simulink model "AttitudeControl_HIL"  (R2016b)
settings: Solver=FixedStepDiscrete  StartTime=0.0  StopTime=10.0  RelTol=1e-3
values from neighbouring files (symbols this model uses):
  DEG2RAD = 0.0174533    [Init_control.m]
  Kd_PITCH_AgngleRate = 0.001    [Init_control.m]
  Kd_ROLL_AgngleRate = 0.001    [Init_control.m]
  Kd_YAW_AngleRate = 0.00    (= 0)    [Init_control.m]
  Ki_PITCH_AgngleRate = 0.02    [Init_control.m]
  Ki_ROLL_AgngleRate = 0.02    [Init_control.m]
  Ki_YAW_AngleRate = 0.01    [Init_control.m]
  Kp_PITCH_AgngleRate = 0.1    [Init_control.m]
  Kp_PITCH_ANGLE = 6.5    [Init_control.m]
  Kp_ROLL_AgngleRate = 0.1    [Init_control.m]
  Kp_ROLL_ANGLE = 6.5    [Init_control.m]
  Kp_YAW_AngleRate = 0.3    [Init_control.m]
  MAX_CONTROL_ANGLE_PITCH = 35    [Init_control.m]
  MAX_CONTROL_ANGLE_RATE_PITCH = 220    [Init_control.m]
  MAX_CONTROL_ANGLE_RATE_ROLL = 220    [Init_control.m]
  MAX_CONTROL_ANGLE_RATE_Y = 200    [Init_control.m]
  MAX_CONTROL_ANGLE_ROLL = 35    [Init_control.m]
  Saturation_I_RP_Max = 0.3    [Init_control.m]
  Saturation_I_RP_Min = -0.3    [Init_control.m]
  Saturation_I_Y_Max = 0.2    [Init_control.m]
  Saturation_I_Y_Min = -0.2    [Init_control.m]
  THR_HOVER = 0.6085    [Init_control.m]
undefined symbols (not defined in the file or in its folder): DiscIntNeverNeededParam, RGBLED_COLOR_ENUM, RGBLED_MODE_ENUM
libraries: simulink x5, pixhawk_slib_sensors_actuators x4, pixhawk_slib_uORB_RW x1

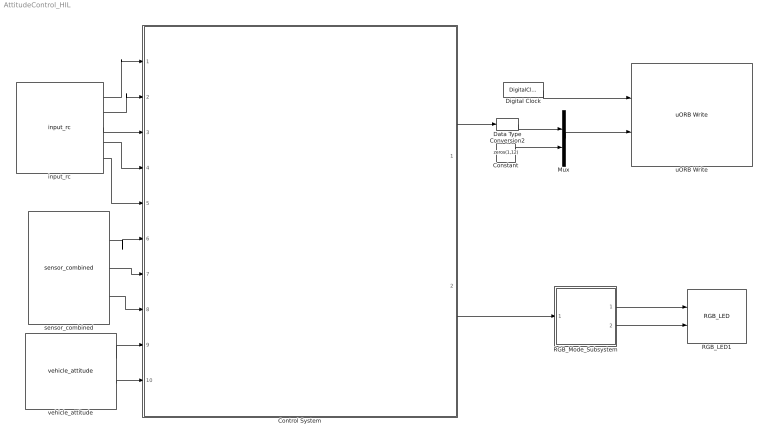
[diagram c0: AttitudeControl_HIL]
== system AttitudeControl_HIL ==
  Constant : Constant  Value=zeros(1,12)
  Control System : Subsystem
  Data Type Conversion2 : DataTypeConversion  OutDataTypeStr=double
  Digital Clock : DigitalClock  SampleTime=-1
  Mux : Mux  Inputs=2
  RGB_LED1 : pixhawk_slib_sensors_actuators/RGB_LED
  RGB_Mode_Subsystem : Subsystem
  input_rc : pixhawk_slib_sensors_actuators/input_rc  sampletime=0.004  channel1=on  channel2=on  channel3=on  channel4=on  channel5=on  channel6=off  channel7=off  channel8=off  ch_count=off  rssi=off  rc_failsafe=off  rc_lost=off  rc_inputsource=off
  sensor_combined : pixhawk_slib_sensors_actuators/sensor_combined  sampletime=0.004  show_mag=off  show_acc=off  show_gyro=on  show_baro=off  show_ts=off
  uORB Write : pixhawk_slib_uORB_RW/uORB Write  uORB_Topic_str='actuator_outputs'  BlockOutputCount=2  OutputBoolean_1=on  uORB_Param_Name1='timestamp'  uORB_Param_Name_DT1=double  VectorScalar_1=1  OutputBoolean_2=on  uORB_Param_Name2='output'  uORB_Param_Name_DT2=double  VectorScalar_2=16  OutputBoolean_3=off  uORB_Param_Name3='timestamp_time'  uORB_Param_Name_DT3=double  VectorScalar_3=1  OutputBoolean_4=off  uORB_Param_Name4='gyro_temp'  uORB_Param_Name_DT4=single  VectorScalar_4=3  OutputBoolean_5=off  uORB_Param_Name5='vel_ned_valid'  uORB_Param_Name_DT5=boolean  VectorScalar_5=1  Ts=-1
  vehicle_attitude : pixhawk_slib_sensors_actuators/vehicle_attitude  sampletime=0.004  show_r=on  show_p=on  show_y=off  show_q=off
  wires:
  sensor_combined/1 -> Control System/6(p)
  sensor_combined/3 -> Control System/8(r)
  vehicle_attitude/1 -> Control System/9(roll)
  vehicle_attitude/2 -> Control System/10(pitch)
  sensor_combined/2 -> Control System/7(q)
  RGB_Mode_Subsystem/1(RGB_MODE) -> RGB_LED1/1
  RGB_Mode_Subsystem/2(RGB_COLOR) -> RGB_LED1/2
  Control System/2(RC_Armed/LED) -> RGB_Mode_Subsystem/1(LED)
  input_rc/1 -> Control System/1(ch1)
  input_rc/2 -> Control System/2(ch2)
  input_rc/3 -> Control System/3(ch3)
  input_rc/4 -> Control System/4(ch4)
  input_rc/5 -> Control System/5(ch5)
  Digital Clock/1 -> uORB Write/1
  Mux/1 -> uORB Write/2
  Control System/1(PWM) -> Data Type Conversion2/1
  Constant/1 -> Mux/2
  Data Type Conversion2/1 -> Mux/1

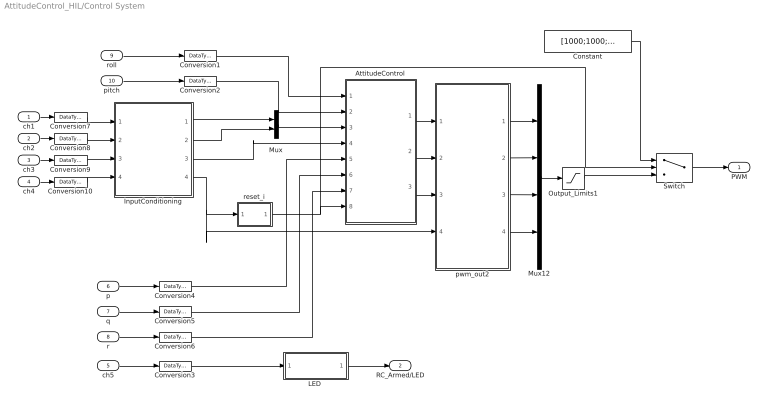
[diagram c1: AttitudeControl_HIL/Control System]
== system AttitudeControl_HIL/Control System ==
  ch1 : Inport  OutDataTypeStr=uint16  PortDimensions=1
  ch2 : Inport  Port=2  OutDataTypeStr=uint16  PortDimensions=1
  ch3 : Inport  Port=3  OutDataTypeStr=uint16  PortDimensions=1
  ch4 : Inport  Port=4  OutDataTypeStr=uint16  PortDimensions=1
  ch5 : Inport  Port=5  OutDataTypeStr=uint16  PortDimensions=1  Interpolate=off
  p : Inport  Port=6  PortDimensions=1
  q : Inport  Port=7  PortDimensions=1
  r : Inport  Port=8  PortDimensions=1
  roll : Inport  Port=9  PortDimensions=1
  pitch : Inport  Port=10  PortDimensions=1
  AttitudeControl : Subsystem
  Constant : Constant  Value=[1000;1000;1000;1000]
  Conversion{1..10} (10 alike) : DataTypeConversion  OutDataTypeStr=double
  InputConditioning : Subsystem
  "LED " : Subsystem
  Mux : Mux  Inputs=2
  Mux12 : Mux
  Output_Limits1 : Saturate  UpperLimit=single(2000)  LowerLimit=single(1000)
  Switch : Switch  Criteria=u2 ~= 0
  pwm_out2 : MATLAB Function  SystemSampleTime=0.004
  reset_i : Subsystem
  PWM : Outport
  RC_Armed/LED : Outport  Port=2  PortDimensions=1
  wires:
  Mux12/1 -> Output_Limits1/1
  AttitudeControl/2(torque_pitch) -> pwm_out2/2(Pitch)
  AttitudeControl/1(torque_roll) -> pwm_out2/1(Roll)
  pwm_out2/1(M1) -> Mux12/1
  pwm_out2/3(M3) -> Mux12/3
  pwm_out2/2(M2) -> Mux12/2
  AttitudeControl/3(torque_yaw) -> pwm_out2/3(Yaw)
  pwm_out2/4(M4) -> Mux12/4
  reset_i/1(Out1) -> AttitudeControl/8(reset_i), Switch/2
  p/1 -> Conversion4/1
  q/1 -> Conversion5/1
  r/1 -> Conversion6/1
  pitch/1 -> Conversion2/1
  roll/1 -> Conversion1/1
  Mux/1 -> AttitudeControl/3(roll_pitch_d)
  "LED "/1(Out1) -> RC_Armed/LED/1
  ch5/1 -> Conversion3/1
  Conversion1/1 -> AttitudeControl/1(phi)
  Conversion2/1 -> AttitudeControl/2(theta)
  Conversion3/1 -> "LED "/1(In1)
  Conversion4/1 -> AttitudeControl/5(p)
  Conversion5/1 -> AttitudeControl/6(q)
  Conversion6/1 -> AttitudeControl/7(r)
  ch3/1 -> Conversion9/1
  ch4/1 -> Conversion10/1
  Conversion10/1 -> InputConditioning/4(r)
  Conversion9/1 -> InputConditioning/3(thrust)
  ch1/1 -> Conversion7/1
  ch2/1 -> Conversion8/1
  InputConditioning/1(Roll) -> Mux/1
  InputConditioning/2(Pitch) -> Mux/2
  InputConditioning/3(Yaw) -> AttitudeControl/4(yawRate_d)
  InputConditioning/4(Thrust) -> pwm_out2/4(Thrust), reset_i/1(In1)
  Conversion7/1 -> InputConditioning/1(roll)
  Conversion8/1 -> InputConditioning/2(pitch)
  Constant/1 -> Switch/1
  Switch/1 -> PWM/1
  Output_Limits1/1 -> Switch/3

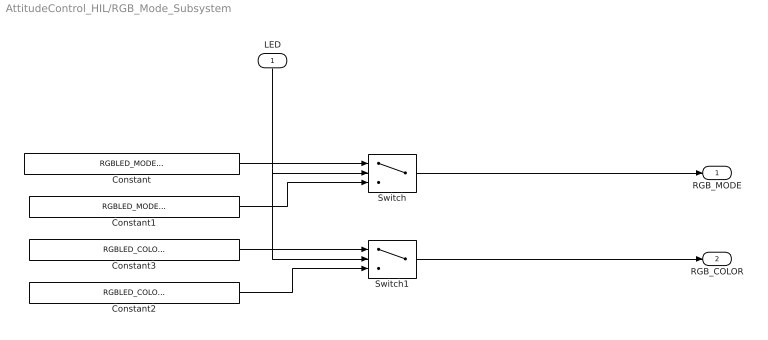
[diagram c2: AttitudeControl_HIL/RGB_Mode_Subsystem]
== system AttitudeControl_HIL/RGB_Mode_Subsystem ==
  LED : Inport
  Constant : Constant  Value=RGBLED_MODE_ENUM.MODE_BLINK_FAST  OutDataTypeStr=Enum: RGBLED_MODE_ENUM
  Constant1 : Constant  Value=RGBLED_MODE_ENUM.MODE_BREATHE  OutDataTypeStr=Enum: RGBLED_MODE_ENUM
  Constant2 : Constant  Value=RGBLED_COLOR_ENUM.COLOR_GREEN  OutDataTypeStr=Enum: RGBLED_COLOR_ENUM
  Constant3 : Constant  Value=RGBLED_COLOR_ENUM.COLOR_RED  OutDataTypeStr=Enum: RGBLED_COLOR_ENUM
  Switch : Switch  Criteria=u2 ~= 0  Threshold=1500  SampleTime=1/2
  Switch1 : Switch  Criteria=u2 ~= 0  Threshold=1500  SampleTime=1/2
  RGB_MODE : Outport
  RGB_COLOR : Outport  Port=2
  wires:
  LED/1 -> Switch1/2, Switch/2
  Constant/1 -> Switch/1
  Constant1/1 -> Switch/3
  Switch/1 -> RGB_MODE/1
  Constant3/1 -> Switch1/1
  Constant2/1 -> Switch1/3
  Switch1/1 -> RGB_COLOR/1

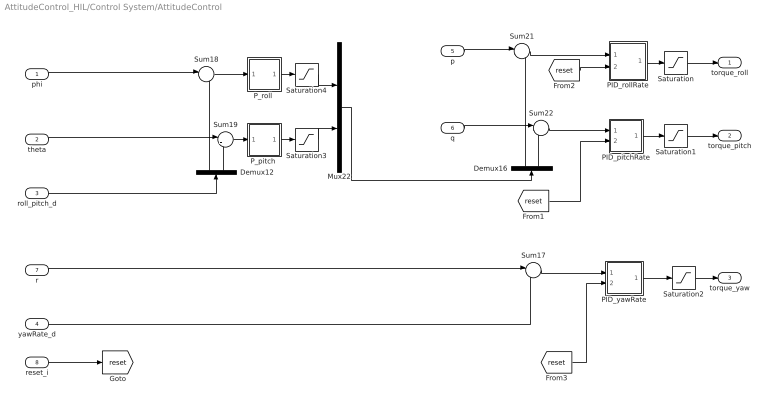
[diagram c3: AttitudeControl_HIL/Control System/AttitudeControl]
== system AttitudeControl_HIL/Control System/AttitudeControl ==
  phi : Inport
  theta : Inport  Port=2
  roll_pitch_d : Inport  Port=3
  yawRate_d : Inport  Port=4
  p : Inport  Port=5
  q : Inport  Port=6
  r : Inport  Port=7
  reset_i : Inport  Port=8
  Demux12 : Demux  Outputs=2
  Demux16 : Demux  Outputs=2
  Mux22 : Mux  Inputs=2
  PID_pitchRate : Subsystem
  PID_rollRate : Subsystem
  PID_yawRate : Subsystem
  "P_pitch " : Subsystem
  "P_roll " : Subsystem
  Saturation : Saturate  UpperLimit=1  LowerLimit=-1
  Saturation1 : Saturate  UpperLimit=1  LowerLimit=-1
  Saturation2 : Saturate
  Saturation3 : Saturate  UpperLimit=MAX_CONTROL_ANGLE_RATE_PITCH  LowerLimit=-MAX_CONTROL_ANGLE_RATE_PITCH
  Saturation4 : Saturate  UpperLimit=MAX_CONTROL_ANGLE_RATE_ROLL  LowerLimit=-MAX_CONTROL_ANGLE_RATE_ROLL
  Sum{17..19,21..22} (5 alike) : Sum  Inputs=|-+
  torque_roll : Outport
  torque_pitch : Outport  Port=2
  torque_yaw : Outport  Port=3
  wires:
  r/1 -> Sum17/1
  Sum19/1 -> "P_pitch "/1(x)
  "P_pitch "/1(y) -> Saturation3/1
  "P_roll "/1(y) -> Saturation4/1
  roll_pitch_d/1 -> Demux12/1
  Demux12/1 -> Sum18/2
  Demux12/2 -> Sum19/2
  phi/1 -> Sum18/1
  theta/1 -> Sum19/1
  Sum18/1 -> "P_roll "/1(x)
  Sum22/1 -> PID_pitchRate/1(x)
  Sum17/1 -> PID_yawRate/1(x)
  p/1 -> Sum21/1
  q/1 -> Sum22/1
  Sum21/1 -> PID_rollRate/1(x)
  Demux16/1 -> Sum21/2
  PID_pitchRate/1(y) -> Saturation1/1
  PID_rollRate/1(y) -> Saturation/1
  PID_yawRate/1(y) -> Saturation2/1
  yawRate_d/1 -> Sum17/2
  reset_i/1 -> [reset]
  [reset] -> PID_rollRate/2(reset_i)
  [reset] -> PID_pitchRate/2(reset_i)
  [reset] -> PID_yawRate/2(reset_i)
  Saturation/1 -> torque_roll/1
  Saturation1/1 -> torque_pitch/1
  Saturation2/1 -> torque_yaw/1
  Mux22/1 -> Demux16/1
  Saturation4/1 -> Mux22/1
  Saturation3/1 -> Mux22/2
  Demux16/2 -> Sum22/2

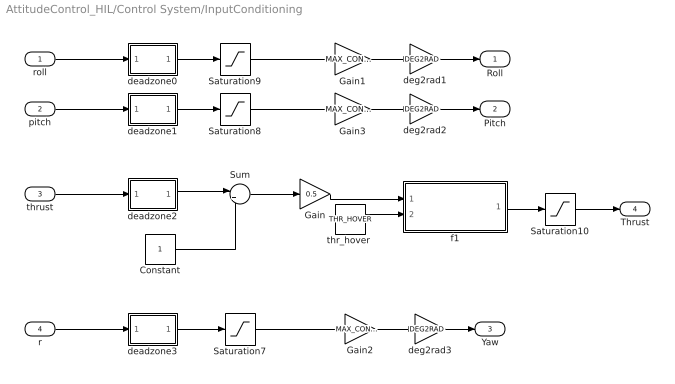
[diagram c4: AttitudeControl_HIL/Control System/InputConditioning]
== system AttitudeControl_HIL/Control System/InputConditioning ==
  roll : Inport
  pitch : Inport  Port=2
  thrust : Inport  Port=3
  r : Inport  Port=4
  Constant : Constant
  Gain : Gain  Gain=0.5
  Gain1 : Gain  Gain=MAX_CONTROL_ANGLE_ROLL  OutDataTypeStr=Inherit: Inherit via back propagation
  Gain2 : Gain  Gain=MAX_CONTROL_ANGLE_RATE_Y
  Gain3 : Gain  Gain=MAX_CONTROL_ANGLE_PITCH  OutDataTypeStr=Inherit: Inherit via back propagation
  Saturation10 : Saturate  UpperLimit=1  LowerLimit=0
  Saturation7 : Saturate  UpperLimit=1  LowerLimit=-1
  Saturation8 : Saturate  UpperLimit=1  LowerLimit=-1
  Saturation9 : Saturate  UpperLimit=1  LowerLimit=-1
  Sum : Sum  Inputs=|++
  deadzone0 : MATLAB Function  TreatAsAtomicUnit=on
  deadzone1 : MATLAB Function  TreatAsAtomicUnit=on
  deadzone2 : MATLAB Function  TreatAsAtomicUnit=on
  deadzone3 : MATLAB Function  TreatAsAtomicUnit=on
  deg2rad1 : Gain  Gain=DEG2RAD
  deg2rad2 : Gain  Gain=DEG2RAD
  deg2rad3 : Gain  Gain=DEG2RAD
  f1 : MATLAB Function  TreatAsAtomicUnit=on
  "thr_hover " : Constant  Value=THR_HOVER
  Roll : Outport
  Pitch : Outport  Port=2
  Yaw : Outport  Port=3
  Thrust : Outport  Port=4
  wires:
  deadzone2/1(y) -> Sum/1
  thrust/1 -> deadzone2/1(u)
  deadzone1/1(y) -> Saturation8/1
  Saturation10/1 -> Thrust/1
  deadzone0/1(y) -> Saturation9/1
  pitch/1 -> deadzone1/1(u)
  Saturation9/1 -> Gain1/1
  Saturation8/1 -> Gain3/1
  Gain3/1 -> deg2rad2/1
  Constant/1 -> Sum/2
  Sum/1 -> Gain/1
  Gain1/1 -> deg2rad1/1
  deg2rad1/1 -> Roll/1
  deg2rad2/1 -> Pitch/1
  Saturation7/1 -> Gain2/1
  deadzone3/1(y) -> Saturation7/1
  r/1 -> deadzone3/1(u)
  Gain2/1 -> deg2rad3/1
  deg2rad3/1 -> Yaw/1
  "thr_hover "/1 -> f1/2(hover)
  Gain/1 -> f1/1(in)
  f1/1(y) -> Saturation10/1
  roll/1 -> deadzone0/1(u)

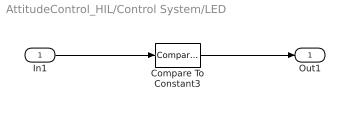
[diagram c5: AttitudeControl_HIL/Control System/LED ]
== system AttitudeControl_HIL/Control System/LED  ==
  In1 : Inport
  Compare To Constant3 : simulink/Logic and Bit Operations/Compare To Constant  relop=>=  const=uint16(1500)  OutDataTypeStr=boolean
  Out1 : Outport
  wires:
  Compare To Constant3/1 -> Out1/1
  In1/1 -> Compare To Constant3/1

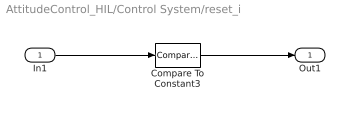
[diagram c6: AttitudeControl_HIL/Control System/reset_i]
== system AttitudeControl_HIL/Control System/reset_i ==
  In1 : Inport
  Compare To Constant3 : simulink/Logic and Bit Operations/Compare To Constant  relop=<=  const=0.2  OutDataTypeStr=boolean
  Out1 : Outport
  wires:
  In1/1 -> Compare To Constant3/1
  Compare To Constant3/1 -> Out1/1

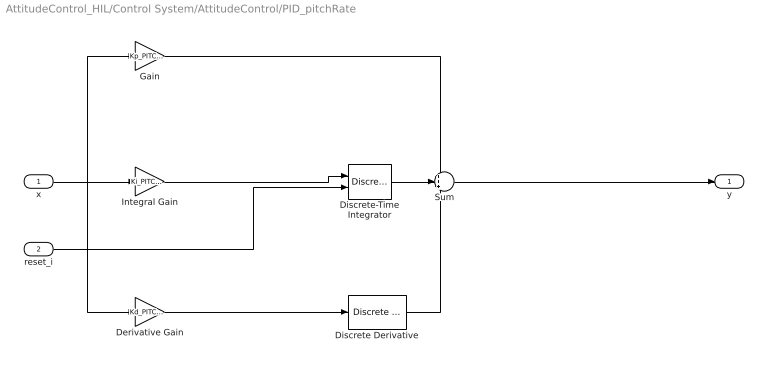
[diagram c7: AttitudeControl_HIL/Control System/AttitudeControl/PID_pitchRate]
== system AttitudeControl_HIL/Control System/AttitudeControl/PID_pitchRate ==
  x : Inport
  reset_i : Inport  Port=2
  Derivative Gain : Gain  DisableCoverage=on  Gain=Kd_PITCH_AgngleRate  ParamMin=-100  ParamMax=100  OutMin=-100  OutMax=100
  Discrete Derivative : simulink/Discrete/Discrete Derivative  gainval=1.0  ICPrevScaledInput=0.0  OutMin=[]  OutMax=[]  OutDataType=fixdt(1, 16)  OutScaling=2^-10  DoSatur=off
  Discrete-Time Integrator : DiscreteIntegrator  ExternalReset=either  InitialConditionSetting=State (most efficient)  SampleTime=-1  LimitOutput=on  UpperSaturationLimit=Saturation_I_RP_Max  LowerSaturationLimit=Saturation_I_RP_Min  ICPrevOutput=DiscIntNeverNeededParam  ICPrevScaledInput=DiscIntNeverNeededParam
  Gain : Gain  Gain=Kp_PITCH_AgngleRate
  Integral Gain : Gain  DisableCoverage=on  Gain=Ki_PITCH_AgngleRate
  Sum : Sum  Inputs=+++
  y : Outport  InitialOutput=0
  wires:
  Discrete-Time Integrator/1 -> Sum/2
  Discrete Derivative/1 -> Sum/3
  Sum/1 -> y/1
  Gain/1 -> Sum/1
  Derivative Gain/1 -> Discrete Derivative/1
  Integral Gain/1 -> Discrete-Time Integrator/1
  x/1 -> Derivative Gain/1, Integral Gain/1, Gain/1
  reset_i/1 -> Discrete-Time Integrator/2

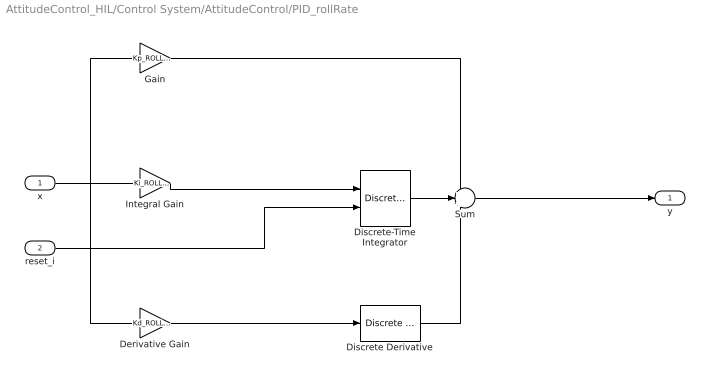
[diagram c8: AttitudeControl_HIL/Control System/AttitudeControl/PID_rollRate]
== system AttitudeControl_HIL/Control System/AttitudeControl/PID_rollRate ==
  x : Inport
  reset_i : Inport  Port=2
  Derivative Gain : Gain  DisableCoverage=on  Gain=Kd_ROLL_AgngleRate  ParamMin=-100  ParamMax=100  OutMin=-100  OutMax=100
  Discrete Derivative : simulink/Discrete/Discrete Derivative  gainval=1.0  ICPrevScaledInput=0.0  OutMin=[]  OutMax=[]  OutDataType=fixdt(1, 16)  OutScaling=2^-10  DoSatur=off
  Discrete-Time Integrator : DiscreteIntegrator  ExternalReset=either  InitialConditionSetting=State (most efficient)  SampleTime=-1  LimitOutput=on  UpperSaturationLimit=Saturation_I_RP_Max  LowerSaturationLimit=Saturation_I_RP_Min  ICPrevOutput=DiscIntNeverNeededParam  ICPrevScaledInput=DiscIntNeverNeededParam
  Gain : Gain  Gain=Kp_ROLL_AgngleRate
  Integral Gain : Gain  DisableCoverage=on  Gain=Ki_ROLL_AgngleRate
  Sum : Sum  Inputs=+++
  y : Outport  InitialOutput=0
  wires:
  x/1 -> Derivative Gain/1, Gain/1, Integral Gain/1
  Integral Gain/1 -> Discrete-Time Integrator/1
  Derivative Gain/1 -> Discrete Derivative/1
  Gain/1 -> Sum/1
  Sum/1 -> y/1
  Discrete Derivative/1 -> Sum/3
  Discrete-Time Integrator/1 -> Sum/2
  reset_i/1 -> Discrete-Time Integrator/2

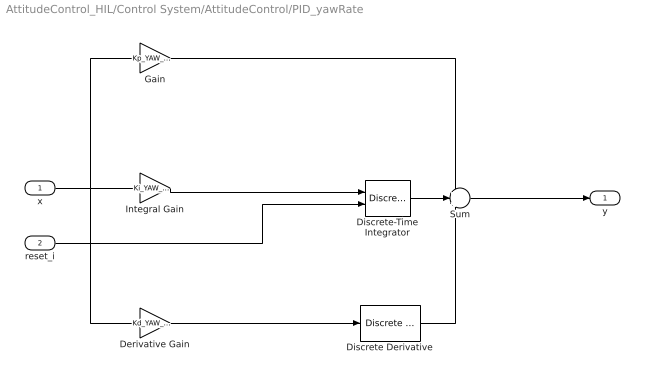
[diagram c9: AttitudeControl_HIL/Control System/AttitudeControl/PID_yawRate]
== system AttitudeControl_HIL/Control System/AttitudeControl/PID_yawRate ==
  x : Inport
  reset_i : Inport  Port=2
  Derivative Gain : Gain  DisableCoverage=on  Gain=Kd_YAW_AngleRate  ParamMin=-100  ParamMax=100  OutMin=-100  OutMax=100
  Discrete Derivative : simulink/Discrete/Discrete Derivative  gainval=1.0  ICPrevScaledInput=0.0  OutMin=[]  OutMax=[]  OutDataType=fixdt(1, 16)  OutScaling=2^-10  DoSatur=off
  Discrete-Time Integrator : DiscreteIntegrator  ExternalReset=either  InitialConditionSetting=State (most efficient)  SampleTime=-1  LimitOutput=on  UpperSaturationLimit=Saturation_I_Y_Max  LowerSaturationLimit=Saturation_I_Y_Min  ICPrevOutput=DiscIntNeverNeededParam  ICPrevScaledInput=DiscIntNeverNeededParam
  Gain : Gain  Gain=Kp_YAW_AngleRate
  Integral Gain : Gain  DisableCoverage=on  Gain=Ki_YAW_AngleRate
  Sum : Sum  Inputs=+++
  y : Outport  InitialOutput=0
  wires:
  x/1 -> Gain/1, Integral Gain/1, Derivative Gain/1
  Integral Gain/1 -> Discrete-Time Integrator/1
  Derivative Gain/1 -> Discrete Derivative/1
  Gain/1 -> Sum/1
  Sum/1 -> y/1
  Discrete Derivative/1 -> Sum/3
  Discrete-Time Integrator/1 -> Sum/2
  reset_i/1 -> Discrete-Time Integrator/2

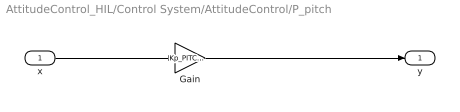
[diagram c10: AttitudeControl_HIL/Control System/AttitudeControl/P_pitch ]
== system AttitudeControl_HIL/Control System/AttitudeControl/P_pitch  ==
  x : Inport
  Gain : Gain  Gain=Kp_PITCH_ANGLE
  y : Outport  InitialOutput=0
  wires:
  x/1 -> Gain/1
  Gain/1 -> y/1

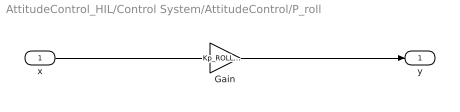
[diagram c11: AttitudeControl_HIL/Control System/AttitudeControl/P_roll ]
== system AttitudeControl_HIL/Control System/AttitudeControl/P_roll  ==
  x : Inport
  Gain : Gain  Gain=Kp_ROLL_ANGLE
  y : Outport  InitialOutput=0
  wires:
  Gain/1 -> y/1
  x/1 -> Gain/1

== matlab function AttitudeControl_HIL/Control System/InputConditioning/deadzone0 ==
function y = fcn(u)
%将遥控输入的范围控制在1100~1900，同时设置一个死区，死区大小为±deadZone
RCMin = 1094;
RCMax = 1934;
RCMid = (RCMin+RCMax)/2;
deadZoneRate = 0.05;
deadZone = deadZoneRate*(RCMax-RCMin);
k=1/(RCMax-RCMid-deadZone);
%限幅
if(u < RCMin)
    u = RCMin;
elseif(u > RCMax)
    u = RCMax;
end
%死区
 if(u > RCMid+deadZone)
    y = (u-RCMid-deadZone)*k;
 elseif(u < RCMid-deadZone)
     y = (u-RCMid+deadZone)*k;
 else
     y = 0;
 end

 end

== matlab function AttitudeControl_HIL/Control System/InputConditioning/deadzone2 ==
function y = fcn(u)
%将遥控输入的范围控制在1100~1900，同时设置一个死区，死区大小为±deadZone
RCMin = 1094;
RCMax = 1934;
RCMid = (RCMin+RCMax)/2;
deadZoneRate = 0.05;
deadZone = deadZoneRate*(RCMax-RCMin);
k=1/(RCMax-RCMid-deadZone);
%限幅
if(u < RCMin)
    u = RCMin;
elseif(u > RCMax)
    u = RCMax;
end
%死区
 if(u > RCMid+deadZone)
    y = (u-RCMid-deadZone)*k;
 elseif(u < RCMid-deadZone)
     y = (u-RCMid+deadZone)*k;
 else
     y = 0;
 end

 end

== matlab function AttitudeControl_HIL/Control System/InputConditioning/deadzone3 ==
function y = fcn(u)
%将遥控输入的范围控制在1100~1900，同时设置一个死区，死区大小为±deadZone
RCMin = 1094;
RCMax = 1934;
RCMid = (RCMin+RCMax)/2;
deadZoneRate = 0.05;
deadZone = deadZoneRate*(RCMax-RCMin);
k=1/(RCMax-RCMid-deadZone);
%限幅
if(u < RCMin)
    u = RCMin;
elseif(u > RCMax)
    u = RCMax;
end
%死区
 if(u > RCMid+deadZone)
    y = (u-RCMid-deadZone)*k;
 elseif(u < RCMid-deadZone)
     y = (u-RCMid+deadZone)*k;
 else
     y = 0;
 end

 end

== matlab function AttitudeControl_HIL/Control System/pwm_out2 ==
function [M1, M2, M3, M4] = motor_mixer(Roll, Pitch, Yaw, Thrust)
%quadrotorX
%3     1
%  \ /
%  / \
%2     4

idle_PWM = 1000;
scale = 1000;

M1 = (Thrust - Roll + Pitch + Yaw) * scale + idle_PWM;
M2 = (Thrust + Roll - Pitch + Yaw) * scale + idle_PWM;
M3 = (Thrust + Roll + Pitch - Yaw) * scale + idle_PWM;
M4 = (Thrust - Roll - Pitch - Yaw) * scale + idle_PWM;

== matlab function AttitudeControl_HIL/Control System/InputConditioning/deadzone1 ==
function y = fcn(u)
%将遥控输入的范围控制在1100~1900，同时设置一个死区，死区大小为±deadZone
RCMin = 1094;
RCMax = 1934;
RCMid = (RCMin+RCMax)/2;
deadZoneRate = 0.05;
deadZone = deadZoneRate*(RCMax-RCMin);
k=1/(RCMax-RCMid-deadZone);
%限幅
if(u < RCMin)
    u = RCMin;
elseif(u > RCMax)
    u = RCMax;
end
%死区
 if(u > RCMid+deadZone)
    y = (u-RCMid-deadZone)*k;
 elseif(u < RCMid-deadZone)
     y = (u-RCMid+deadZone)*k;
 else
     y = 0;
 end

 end

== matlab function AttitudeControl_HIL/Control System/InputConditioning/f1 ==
function y = thr_curve(in,hover)
%输入油门归一化后为0~1，中点为0.5
%经过这个函数，油门在中间位置时，输出为悬停油门 hover
if in < 0.5
	y=2 * in * hover;
else
	y=hover + 2 * (in - 0.5) * (1.0 - hover);
end
